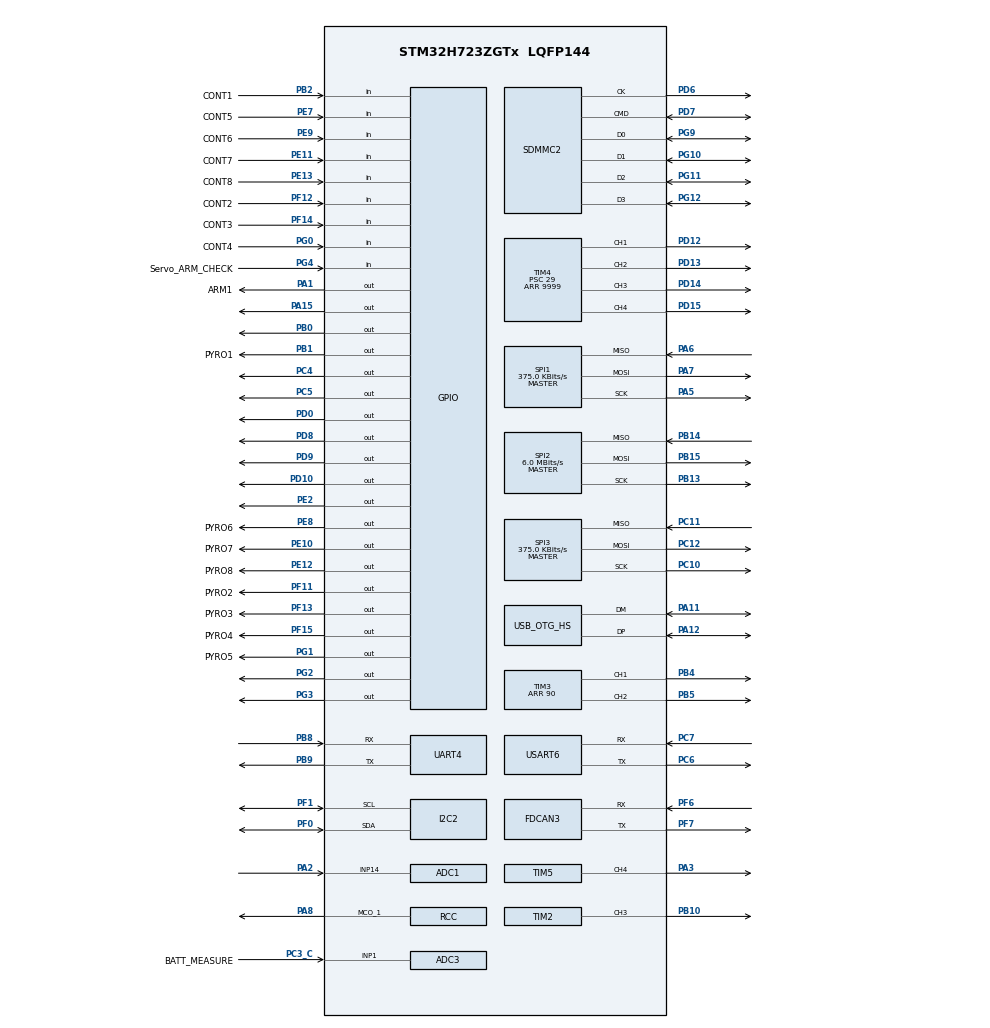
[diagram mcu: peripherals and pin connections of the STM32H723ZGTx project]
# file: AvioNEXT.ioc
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ADC1.Channel-0\#ChannelRegularConversion=ADC_CHANNEL_14
ADC1.ClockPrescaler=ADC_CLOCK_ASYNC_DIV256
ADC1.ClockPrescalerADC3=ADC_CLOCK_ASYNC_DIV256
ADC1.ContinuousConvMode=DISABLE
ADC1.NbrOfConversionFlag=1
ADC1.OffsetNumber-0\#ChannelRegularConversion=ADC_OFFSET_NONE
ADC1.OffsetSignedSaturation-0\#ChannelRegularConversion=DISABLE
ADC1.Rank-0\#ChannelRegularConversion=1
ADC1.SamplingTime-0\#ChannelRegularConversion=ADC_SAMPLETIME_16CYCLES_5
ADC1.master=1
ADC3.Channel-0\#ChannelRegularConversion=ADC_CHANNEL_1
ADC3.ClockPrescaler=ADC_CLOCK_ASYNC_DIV256
ADC3.ClockPrescalerADC3=ADC_CLOCK_ASYNC_DIV256
ADC3.ContinuousConvMode=DISABLE
ADC3.DMAContinuousRequests=ENABLE
ADC3.DiscontinuousConvMode=DISABLE
ADC3.NbrOfConversion=1
ADC3.NbrOfConversionFlag=1
ADC3.OffsetNumber-0\#ChannelRegularConversion=ADC_OFFSET_NONE
ADC3.OffsetSign-0\#ChannelRegularConversion=ADC3_OFFSET_SIGN_NEGATIVE
ADC3.Rank-0\#ChannelRegularConversion=1
ADC3.SamplingTime-0\#ChannelRegularConversion=ADC3_SAMPLETIME_2CYCLES_5
Dma.ADC1.5.Direction=DMA_PERIPH_TO_MEMORY
Dma.ADC1.5.EventEnable=DISABLE
Dma.ADC1.5.FIFOMode=DMA_FIFOMODE_DISABLE
Dma.ADC1.5.Instance=DMA1_Stream5
Dma.ADC1.5.MemDataAlignment=DMA_MDATAALIGN_HALFWORD
Dma.ADC1.5.MemInc=DMA_MINC_ENABLE
Dma.ADC1.5.Mode=DMA_NORMAL
Dma.ADC1.5.PeriphDataAlignment=DMA_PDATAALIGN_HALFWORD
Dma.ADC1.5.PeriphInc=DMA_PINC_DISABLE
Dma.ADC1.5.Polarity=HAL_DMAMUX_REQ_GEN_RISING
Dma.ADC1.5.Priority=DMA_PRIORITY_LOW
Dma.ADC1.5.RequestNumber=1
Dma.ADC1.5.SignalID=NONE
Dma.ADC1.5.SyncEnable=DISABLE
Dma.ADC1.5.SyncPolarity=HAL_DMAMUX_SYNC_NO_EVENT
Dma.ADC1.5.SyncRequestNumber=1
Dma.ADC1.5.SyncSignalID=NONE
Dma.ADC3.6.Direction=DMA_PERIPH_TO_MEMORY
Dma.ADC3.6.EventEnable=DISABLE
Dma.ADC3.6.FIFOMode=DMA_FIFOMODE_DISABLE
Dma.ADC3.6.Instance=DMA2_Stream7
Dma.ADC3.6.MemDataAlignment=DMA_MDATAALIGN_HALFWORD
Dma.ADC3.6.MemInc=DMA_MINC_ENABLE
Dma.ADC3.6.Mode=DMA_CIRCULAR
Dma.ADC3.6.PeriphDataAlignment=DMA_PDATAALIGN_HALFWORD
Dma.ADC3.6.PeriphInc=DMA_PINC_DISABLE
Dma.ADC3.6.Polarity=HAL_DMAMUX_REQ_GEN_RISING
Dma.ADC3.6.Priority=DMA_PRIORITY_MEDIUM
Dma.ADC3.6.RequestNumber=1
Dma.ADC3.6.SignalID=NONE
Dma.ADC3.6.SyncEnable=DISABLE
Dma.ADC3.6.SyncPolarity=HAL_DMAMUX_SYNC_NO_EVENT
Dma.ADC3.6.SyncRequestNumber=1
Dma.ADC3.6.SyncSignalID=NONE
Dma.Request0=TIM4_CH3
Dma.Request1=TIM2_CH3
Dma.Request2=TIM5_CH4
Dma.Request3=TIM3_CH2
Dma.Request4=TIM3_CH1
Dma.Request5=ADC1
Dma.Request6=ADC3
Dma.TIM2_CH3.1.Direction=DMA_MEMORY_TO_PERIPH
Dma.TIM2_CH3.1.EventEnable=DISABLE
Dma.TIM2_CH3.1.FIFOMode=DMA_FIFOMODE_DISABLE
Dma.TIM2_CH3.1.Instance=DMA1_Stream1
Dma.TIM2_CH3.1.MemDataAlignment=DMA_MDATAALIGN_WORD
Dma.TIM2_CH3.1.MemInc=DMA_MINC_ENABLE
Dma.TIM2_CH3.1.Mode=DMA_NORMAL
Dma.TIM2_CH3.1.PeriphDataAlignment=DMA_PDATAALIGN_WORD
Dma.TIM2_CH3.1.PeriphInc=DMA_PINC_DISABLE
Dma.TIM2_CH3.1.Polarity=HAL_DMAMUX_REQ_GEN_RISING
Dma.TIM2_CH3.1.Priority=DMA_PRIORITY_LOW
Dma.TIM2_CH3.1.RequestNumber=1
Dma.TIM2_CH3.1.SignalID=NONE
Dma.TIM2_CH3.1.SyncEnable=DISABLE
Dma.TIM2_CH3.1.SyncPolarity=HAL_DMAMUX_SYNC_NO_EVENT
Dma.TIM2_CH3.1.SyncRequestNumber=1
Dma.TIM2_CH3.1.SyncSignalID=NONE
Dma.TIM3_CH1.4.Direction=DMA_MEMORY_TO_PERIPH
Dma.TIM3_CH1.4.EventEnable=DISABLE
Dma.TIM3_CH1.4.FIFOMode=DMA_FIFOMODE_DISABLE
Dma.TIM3_CH1.4.Instance=DMA1_Stream4
Dma.TIM3_CH1.4.MemDataAlignment=DMA_MDATAALIGN_WORD
Dma.TIM3_CH1.4.MemInc=DMA_MINC_ENABLE
Dma.TIM3_CH1.4.Mode=DMA_NORMAL
Dma.TIM3_CH1.4.PeriphDataAlignment=DMA_PDATAALIGN_WORD
Dma.TIM3_CH1.4.PeriphInc=DMA_PINC_DISABLE
Dma.TIM3_CH1.4.Polarity=HAL_DMAMUX_REQ_GEN_RISING
Dma.TIM3_CH1.4.Priority=DMA_PRIORITY_LOW
Dma.TIM3_CH1.4.RequestNumber=1
Dma.TIM3_CH1.4.SignalID=NONE
Dma.TIM3_CH1.4.SyncEnable=DISABLE
Dma.TIM3_CH1.4.SyncPolarity=HAL_DMAMUX_SYNC_NO_EVENT
Dma.TIM3_CH1.4.SyncRequestNumber=1
Dma.TIM3_CH1.4.SyncSignalID=NONE
Dma.TIM3_CH2.3.Direction=DMA_MEMORY_TO_PERIPH
Dma.TIM3_CH2.3.EventEnable=DISABLE
Dma.TIM3_CH2.3.FIFOMode=DMA_FIFOMODE_DISABLE
Dma.TIM3_CH2.3.Instance=DMA1_Stream3
Dma.TIM3_CH2.3.MemDataAlignment=DMA_MDATAALIGN_WORD
Dma.TIM3_CH2.3.MemInc=DMA_MINC_ENABLE
Dma.TIM3_CH2.3.Mode=DMA_NORMAL
Dma.TIM3_CH2.3.PeriphDataAlignment=DMA_PDATAALIGN_WORD
Dma.TIM3_CH2.3.PeriphInc=DMA_PINC_DISABLE
Dma.TIM3_CH2.3.Polarity=HAL_DMAMUX_REQ_GEN_RISING
Dma.TIM3_CH2.3.Priority=DMA_PRIORITY_LOW
Dma.TIM3_CH2.3.RequestNumber=1
Dma.TIM3_CH2.3.SignalID=NONE
Dma.TIM3_CH2.3.SyncEnable=DISABLE
Dma.TIM3_CH2.3.SyncPolarity=HAL_DMAMUX_SYNC_NO_EVENT
Dma.TIM3_CH2.3.SyncRequestNumber=1
Dma.TIM3_CH2.3.SyncSignalID=NONE
Dma.TIM4_CH3.0.Direction=DMA_MEMORY_TO_PERIPH
Dma.TIM4_CH3.0.EventEnable=DISABLE
Dma.TIM4_CH3.0.FIFOMode=DMA_FIFOMODE_DISABLE
Dma.TIM4_CH3.0.Instance=DMA1_Stream0
Dma.TIM4_CH3.0.MemDataAlignment=DMA_MDATAALIGN_WORD
Dma.TIM4_CH3.0.MemInc=DMA_MINC_ENABLE
Dma.TIM4_CH3.0.Mode=DMA_NORMAL
Dma.TIM4_CH3.0.PeriphDataAlignment=DMA_PDATAALIGN_WORD
Dma.TIM4_CH3.0.PeriphInc=DMA_PINC_DISABLE
Dma.TIM4_CH3.0.Polarity=HAL_DMAMUX_REQ_GEN_RISING
Dma.TIM4_CH3.0.Priority=DMA_PRIORITY_LOW
Dma.TIM4_CH3.0.RequestNumber=1
Dma.TIM4_CH3.0.SignalID=NONE
Dma.TIM4_CH3.0.SyncEnable=DISABLE
Dma.TIM4_CH3.0.SyncPolarity=HAL_DMAMUX_SYNC_NO_EVENT
Dma.TIM4_CH3.0.SyncRequestNumber=1
Dma.TIM4_CH3.0.SyncSignalID=NONE
Dma.TIM5_CH4.2.Direction=DMA_MEMORY_TO_PERIPH
Dma.TIM5_CH4.2.EventEnable=DISABLE
Dma.TIM5_CH4.2.FIFOMode=DMA_FIFOMODE_DISABLE
Dma.TIM5_CH4.2.Instance=DMA1_Stream2
Dma.TIM5_CH4.2.MemDataAlignment=DMA_MDATAALIGN_WORD
Dma.TIM5_CH4.2.MemInc=DMA_MINC_ENABLE
Dma.TIM5_CH4.2.Mode=DMA_NORMAL
Dma.TIM5_CH4.2.PeriphDataAlignment=DMA_PDATAALIGN_WORD
Dma.TIM5_CH4.2.PeriphInc=DMA_PINC_DISABLE
Dma.TIM5_CH4.2.Polarity=HAL_DMAMUX_REQ_GEN_RISING
Dma.TIM5_CH4.2.Priority=DMA_PRIORITY_LOW
Dma.TIM5_CH4.2.RequestNumber=1
Dma.TIM5_CH4.2.SignalID=NONE
Dma.TIM5_CH4.2.SyncEnable=DISABLE
Dma.TIM5_CH4.2.SyncPolarity=HAL_DMAMUX_SYNC_NO_EVENT
Dma.TIM5_CH4.2.SyncRequestNumber=1
Dma.TIM5_CH4.2.SyncSignalID=NONE
FATFS.USE_DMA_CODE_SD=1
FATFS._MAX_SS=4096
FATFS._USE_LFN=1
FDCAN3.CalculateBaudRateNominal=500000
FDCAN3.CalculateTimeBitNominal=2000
FDCAN3.CalculateTimeQuantumNominal=400.0
FDCAN3.NominalPrescaler=20
FDCAN3.NominalTimeSeg1=2
FDCAN3.NominalTimeSeg2=2
FDCAN3.RxFifo0ElmtsNbr=1
I2C2.Timing=0x20303E5D
Mcu.Family=STM32H7
Mcu.Name=STM32H723ZGTx
Mcu.Package=LQFP144
NVIC.DMA1_Stream0_IRQn=true\:0\:0\:false\:false\:true\:false\:true\:true
NVIC.DMA1_Stream1_IRQn=true\:0\:0\:false\:false\:true\:false\:true\:true
NVIC.DMA1_Stream2_IRQn=true\:0\:0\:false\:false\:true\:false\:true\:true
NVIC.DMA1_Stream3_IRQn=true\:0\:0\:false\:false\:true\:false\:true\:true
NVIC.DMA1_Stream4_IRQn=true\:0\:0\:false\:false\:true\:false\:true\:true
NVIC.DMA1_Stream5_IRQn=true\:0\:0\:false\:false\:true\:false\:true\:true
NVIC.DMA2_Stream7_IRQn=true\:0\:0\:false\:false\:true\:false\:true\:true
NVIC.FDCAN3_IT0_IRQn=true\:0\:0\:false\:false\:true\:true\:true\:true
NVIC.I2C2_EV_IRQn=true\:1\:0\:true\:false\:true\:true\:true\:true
NVIC.OTG_HS_IRQn=true\:0\:0\:false\:false\:true\:false\:true\:true
NVIC.PriorityGroup=NVIC_PRIORITYGROUP_4
NVIC.SDMMC2_IRQn=true\:0\:0\:false\:false\:true\:true\:true\:true
NVIC.TIM4_IRQn=true\:0\:0\:false\:false\:true\:true\:true\:true
PA0.Signal=S_TIM2_CH1_ETR
PA1.GPIO_Label=ARM1
PA1.Signal=GPIO_Output
PA11.Mode=Device_Only_FS
PA11.Signal=USB_OTG_HS_DM
PA12.Mode=Device_Only_FS
PA12.Signal=USB_OTG_HS_DP
PA13(JTMS/SWDIO).Mode=Serial_Wire
PA13(JTMS/SWDIO).Signal=DEBUG_JTMS-SWDIO
PA14(JTCK/SWCLK).Mode=Serial_Wire
PA14(JTCK/SWCLK).Signal=DEBUG_JTCK-SWCLK
PA15(JTDI).Signal=GPIO_Output
PA2.Signal=ADCx_INP14
PA3.GPIO_PuPd=GPIO_PULLDOWN
PA3.Signal=S_TIM5_CH4
PA5.Mode=Full_Duplex_Master
PA5.Signal=SPI1_SCK
PA6.Mode=Full_Duplex_Master
PA6.Signal=SPI1_MISO
PA7.Mode=Full_Duplex_Master
PA7.Signal=SPI1_MOSI
PA8.Mode=Clock-out-1
PA8.Signal=RCC_MCO_1
PB0.Signal=GPIO_Output
PB1.GPIO_Label=PYRO1
PB1.Signal=GPIO_Output
PB10.GPIO_PuPd=GPIO_PULLDOWN
PB10.Signal=S_TIM2_CH3
PB13.Mode=Full_Duplex_Master
PB13.Signal=SPI2_SCK
PB14.Mode=Full_Duplex_Master
PB14.Signal=SPI2_MISO
PB15.Mode=Full_Duplex_Master
PB15.Signal=SPI2_MOSI
PB2.GPIO_Label=CONT1
PB2.GPIO_PuPd=GPIO_PULLUP
PB2.Signal=GPIO_Input
PB4(NJTRST).GPIO_PuPd=GPIO_PULLDOWN
PB4(NJTRST).Signal=S_TIM3_CH1
PB5.GPIO_PuPd=GPIO_PULLDOWN
PB5.Signal=S_TIM3_CH2
PB8.Mode=Asynchronous
PB8.Signal=UART4_RX
PB9.Mode=Asynchronous
PB9.Signal=UART4_TX
PC10.Mode=Full_Duplex_Master
PC10.Signal=SPI3_SCK
PC11.Mode=Full_Duplex_Master
PC11.Signal=SPI3_MISO
PC12.Mode=Full_Duplex_Master
PC12.Signal=SPI3_MOSI
PC3_C.GPIO_Label=BATT_MEASURE
PC3_C.Mode=IN1-Single-Ended
PC3_C.Signal=ADC3_INP1
PC4.Signal=GPIO_Output
PC5.Signal=GPIO_Output
PC6.Mode=Asynchronous
PC6.Signal=USART6_TX
PC7.Mode=Asynchronous
PC7.Signal=USART6_RX
PD0.Signal=GPIO_Output
PD10.PinState=GPIO_PIN_SET
PD10.Signal=GPIO_Output
PD12.Signal=S_TIM4_CH1
PD13.Signal=S_TIM4_CH2
PD14.GPIO_PuPd=GPIO_PULLDOWN
PD14.Signal=S_TIM4_CH3
PD15.Signal=S_TIM4_CH4
PD6.Mode=SD_4_bits_Wide_bus
PD6.Signal=SDMMC2_CK
PD7.GPIO_PuPd=GPIO_PULLUP
PD7.Mode=SD_4_bits_Wide_bus
PD7.Signal=SDMMC2_CMD
PD8.PinState=GPIO_PIN_SET
PD8.Signal=GPIO_Output
PD9.PinState=GPIO_PIN_SET
PD9.Signal=GPIO_Output
PE10.GPIO_Label=PYRO7
PE10.Signal=GPIO_Output
PE11.GPIO_Label=CONT7
PE11.GPIO_PuPd=GPIO_PULLUP
PE11.Signal=GPIO_Input
PE12.GPIO_Label=PYRO8
PE12.Signal=GPIO_Output
PE13.GPIO_Label=CONT8
PE13.GPIO_PuPd=GPIO_PULLUP
PE13.Signal=GPIO_Input
PE2.PinState=GPIO_PIN_RESET
PE2.Signal=GPIO_Output
PE7.GPIO_Label=CONT5
PE7.GPIO_PuPd=GPIO_PULLUP
PE7.Signal=GPIO_Input
PE8.GPIO_Label=PYRO6
PE8.Signal=GPIO_Output
PE9.GPIO_Label=CONT6
PE9.GPIO_PuPd=GPIO_PULLUP
PE9.Signal=GPIO_Input
PF0.Mode=I2C
PF0.Signal=I2C2_SDA
PF1.Mode=I2C
PF1.Signal=I2C2_SCL
PF11.GPIO_Label=PYRO2
PF11.Signal=GPIO_Output
PF12.GPIO_Label=CONT2
PF12.GPIO_PuPd=GPIO_PULLUP
PF12.Signal=GPIO_Input
PF13.GPIO_Label=PYRO3
PF13.Signal=GPIO_Output
PF14.GPIO_Label=CONT3
PF14.GPIO_PuPd=GPIO_PULLUP
PF14.Signal=GPIO_Input
PF15.GPIO_Label=PYRO4
PF15.Signal=GPIO_Output
PF6.Mode=FDCAN_Activate
PF6.Signal=FDCAN3_RX
PF7.Mode=FDCAN_Activate
PF7.Signal=FDCAN3_TX
PG0.GPIO_Label=CONT4
PG0.GPIO_PuPd=GPIO_PULLUP
PG0.Signal=GPIO_Input
PG1.GPIO_Label=PYRO5
PG1.Signal=GPIO_Output
PG10.Mode=SD_4_bits_Wide_bus
PG10.Signal=SDMMC2_D1
PG11.Mode=SD_4_bits_Wide_bus
PG11.Signal=SDMMC2_D2
PG12.Mode=SD_4_bits_Wide_bus
PG12.Signal=SDMMC2_D3
PG2.Signal=GPIO_Output
PG3.Signal=GPIO_Output
PG4.GPIO_Label=Servo_ARM_CHECK
PG4.Signal=GPIO_Input
PG9.GPIO_PuPd=GPIO_PULLUP
PG9.Mode=SD_4_bits_Wide_bus
PG9.Signal=SDMMC2_D0
ProjectManager.HeapSize=0x400
ProjectManager.StackSize=0x800
ProjectManager.TargetToolchain=STM32CubeIDE
RCC.ADCFreq_Value=48000000
RCC.APB1Freq_Value=50000000
RCC.APB2Freq_Value=50000000
RCC.APB3Freq_Value=100000000
RCC.APB4Freq_Value=100000000
RCC.CortexFreq_Value=200000000
RCC.D1PPRE=RCC_APB3_DIV2
RCC.D2PPRE1=RCC_APB1_DIV4
RCC.D2PPRE2=RCC_APB2_DIV4
RCC.D3PPRE=RCC_APB4_DIV2
RCC.DIVM1=4
RCC.DIVM2=4
RCC.DIVN1=12
RCC.DIVN2=12
RCC.DIVP1=1
RCC.DIVP2=4
RCC.DIVQ1=4
RCC.EnableHSE-ClockTree=true
RCC.HCLKFreq_Value=200000000
RCC.HSE_VALUE=50000000
RCC.PLL2FRACN=0
RCC.PLL2_VCO_SEL-AdvancedSettings=RCC_PLL2VCOMEDIUM
RCC.PLL3FRACN=0
RCC.PLL3_VCO_SEL-AdvancedSettings=RCC_PLL3VCOMEDIUM
RCC.PLLFRACN=4096
RCC.SPI123CLockSelection=RCC_SPI123CLKSOURCE_PLL2
RCC.SYSCLKFreq_VALUE=200000000
RCC.SYSCLKSource=RCC_SYSCLKSOURCE_PLLCLK
RCC.USBCLockSelection=RCC_USBCLKSOURCE_HSI48
RCC.USBFreq_Value=48000000
SDMMC2.ClockDiv=8
SH.ADCx_INP14.0=ADC1_INP14,IN14-Single-Ended
SH.S_TIM2_CH1_ETR.0=TIM2_CH1
SH.S_TIM2_CH3.0=TIM2_CH3,PWM Generation3 CH3
SH.S_TIM3_CH1.0=TIM3_CH1,PWM Generation1 CH1
SH.S_TIM3_CH2.0=TIM3_CH2,PWM Generation2 CH2
SH.S_TIM4_CH1.0=TIM4_CH1,PWM Generation1 CH1
SH.S_TIM4_CH2.0=TIM4_CH2,PWM Generation2 CH2
SH.S_TIM4_CH3.0=TIM4_CH3,PWM Generation3 CH3
SH.S_TIM4_CH4.0=TIM4_CH4,PWM Generation4 CH4
SH.S_TIM5_CH4.0=TIM5_CH4,PWM Generation4 CH4
SPI1.BaudRatePrescaler=SPI_BAUDRATEPRESCALER_128
SPI1.CalculateBaudRate=375.0 KBits/s
SPI1.DataSize=SPI_DATASIZE_8BIT
SPI1.Direction=SPI_DIRECTION_2LINES
SPI1.Mode=SPI_MODE_MASTER
SPI1.VirtualType=VM_MASTER
SPI2.BaudRatePrescaler=SPI_BAUDRATEPRESCALER_8
SPI2.CalculateBaudRate=6.0 MBits/s
SPI2.DataSize=SPI_DATASIZE_8BIT
SPI2.Direction=SPI_DIRECTION_2LINES
SPI2.Mode=SPI_MODE_MASTER
SPI2.VirtualType=VM_MASTER
SPI3.BaudRatePrescaler=SPI_BAUDRATEPRESCALER_128
SPI3.CalculateBaudRate=375.0 KBits/s
SPI3.DataSize=SPI_DATASIZE_8BIT
SPI3.Direction=SPI_DIRECTION_2LINES
SPI3.Mode=SPI_MODE_MASTER
SPI3.VirtualType=VM_MASTER
TIM13.Prescaler=99
TIM2.Channel-PWM\ Generation3\ CH3=TIM_CHANNEL_3
TIM2.Period=90
TIM3.Channel-PWM\ Generation1\ CH1=TIM_CHANNEL_1
TIM3.Channel-PWM\ Generation2\ CH2=TIM_CHANNEL_2
TIM3.Period=90
TIM4.Channel-PWM\ Generation1\ CH1=TIM_CHANNEL_1
TIM4.Channel-PWM\ Generation2\ CH2=TIM_CHANNEL_2
TIM4.Channel-PWM\ Generation3\ CH3=TIM_CHANNEL_3
TIM4.Channel-PWM\ Generation4\ CH4=TIM_CHANNEL_4
TIM4.OCFastMode_PWM-PWM\ Generation3\ CH3=TIM_OCFAST_DISABLE
TIM4.Period=9999
TIM4.Prescaler=29
TIM5.Channel-PWM\ Generation4\ CH4=TIM_CHANNEL_4
TIM5.Period=90
USART6.VirtualMode-Asynchronous=VM_ASYNC
USB_DEVICE.CLASS_NAME_HS=CDC
USB_DEVICE.MANUFACTURER_STRING=ARC
USB_DEVICE.PRODUCT_STRING_CDC_HS=AvioNEXT Flight Computer
USB_DEVICE.VirtualMode=Cdc
USB_DEVICE.VirtualModeHS=Cdc_HS
USB_OTG_HS.VirtualMode-Device_Only_FS=Device_Only_FS
VP_FATFS_VS_SDIO.Mode=SDIO
VP_TIM13_VS_ClockSourceINT.Mode=Enable_Timer
VP_USB_DEVICE_VS_USB_DEVICE_CDC_HS.Mode=CDC_HS
board=custom

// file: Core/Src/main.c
/* USER CODE BEGIN Header */
/**
 ******************************************************************************
 * @file           : main.c
 * @brief          : Main program body
 ******************************************************************************
 * @attention
 *
 * Copyright (c) 2024 STMicroelectronics.
 * All rights reserved.
 *
 * This software is licensed under terms that can be found in the LICENSE file
 * in the root directory of this software component.
 * If no LICENSE file comes with this software, it is provided AS-IS.
 *
 ******************************************************************************
 */
/* USER CODE END Header */
#include "main.h"
#include "fatfs.h"
#include "usb_device.h"

/* USER CODE BEGIN Includes */
//#include "AvioNEXT.h"
//#include "LG_IMU.h"
//#include "max_m10s.h"
//#include "StatusDisplay.h"
#include "LoRA.h"
/* USER CODE END Includes */

/* USER CODE BEGIN PD */

uint16_t DMA_data;

uint16_t read_Data;
/* USER CODE END PD */

ADC_HandleTypeDef hadc1;
ADC_HandleTypeDef hadc3;
DMA_HandleTypeDef hdma_adc1;
DMA_HandleTypeDef hdma_adc3;

FDCAN_HandleTypeDef hfdcan3;

I2C_HandleTypeDef hi2c2;

SD_HandleTypeDef hsd2;

SPI_HandleTypeDef hspi1;
SPI_HandleTypeDef hspi2;
SPI_HandleTypeDef hspi3;

TIM_HandleTypeDef htim2;
TIM_HandleTypeDef htim3;
TIM_HandleTypeDef htim4;
TIM_HandleTypeDef htim5;
TIM_HandleTypeDef htim13;
DMA_HandleTypeDef hdma_tim2_ch3;
DMA_HandleTypeDef hdma_tim3_ch2;
DMA_HandleTypeDef hdma_tim3_ch1;
DMA_HandleTypeDef hdma_tim4_ch3;
DMA_HandleTypeDef hdma_tim5_ch4;

UART_HandleTypeDef huart4;
UART_HandleTypeDef huart6;

void SystemClock_Config(void);
void PeriphCommonClock_Config(void);
static void MX_GPIO_Init(void);
static void MX_DMA_Init(void);
static void MX_SPI3_Init(void);
static void MX_FDCAN3_Init(void);
static void MX_USART6_UART_Init(void);
static void MX_ADC1_Init(void);
static void MX_TIM4_Init(void);
static void MX_ADC3_Init(void);
static void MX_SPI2_Init(void);
static void MX_I2C2_Init(void);
static void MX_TIM2_Init(void);
static void MX_TIM5_Init(void);
static void MX_TIM3_Init(void);
static void MX_SPI1_Init(void);
static void MX_UART4_Init(void);
static void MX_SDMMC2_SD_Init(void);
static void MX_TIM13_Init(void);

int main(void)
{

  /* MCU Configuration--------------------------------------------------------*/

  /* Reset of all peripherals, Initializes the Flash interface and the Systick. */
  HAL_Init();

  /* Configure the system clock */
  SystemClock_Config();

/* Configure the peripherals common clocks */
  PeriphCommonClock_Config();

  /* Initialize all configured peripherals */
  MX_GPIO_Init();
  MX_DMA_Init();
  MX_SPI3_Init();
  MX_FDCAN3_Init();
  MX_USART6_UART_Init();
  MX_ADC1_Init();
  MX_TIM4_Init();
  MX_ADC3_Init();
  MX_SPI2_Init();
  MX_I2C2_Init();
  MX_TIM2_Init();
  MX_TIM5_Init();
  MX_TIM3_Init();
  MX_USB_DEVICE_Init();
  MX_SPI1_Init();
  MX_UART4_Init();
  MX_FATFS_Init();
  MX_SDMMC2_SD_Init();
  MX_TIM13_Init();
  /* USER CODE BEGIN 2 */
  LoRA_begin(86000000);

  /* USER CODE END 2 */

  /* Infinite loop */
  /* USER CODE BEGIN WHILE */
	while (1) {
		char LoRA_data[255];

		if(recv_packet(LoRA_data, 255)){
			char print_data[400];
			sprintf(print_data, "\nRadio Packet received:\n%s\n----------------", LoRA_data);
			CDC_Transmit_HS(print_data, strlen(print_data));
		}
		HAL_Delay(100);
	}

    /* USER CODE END WHILE */

}

void SystemClock_Config(void)
{
  RCC_OscInitTypeDef RCC_OscInitStruct = {0};
  RCC_ClkInitTypeDef RCC_ClkInitStruct = {0};

  /** Supply configuration update enable
  */
  HAL_PWREx_ConfigSupply(PWR_LDO_SUPPLY);

  /** Configure the main internal regulator output voltage
  */
  __HAL_PWR_VOLTAGESCALING_CONFIG(PWR_REGULATOR_VOLTAGE_SCALE2);

  while(!__HAL_PWR_GET_FLAG(PWR_FLAG_VOSRDY)) {}

  /** Initializes the RCC Oscillators according to the specified parameters
  * in the RCC_OscInitTypeDef structure.
  */
  RCC_OscInitStruct.OscillatorType = RCC_OSCILLATORTYPE_HSI48|RCC_OSCILLATORTYPE_HSI;
  RCC_OscInitStruct.HSIState = RCC_HSI_DIV1;
  RCC_OscInitStruct.HSICalibrationValue = 64;
  RCC_OscInitStruct.HSI48State = RCC_HSI48_ON;
  RCC_OscInitStruct.PLL.PLLState = RCC_PLL_ON;
  RCC_OscInitStruct.PLL.PLLSource = RCC_PLLSOURCE_HSI;
  RCC_OscInitStruct.PLL.PLLM = 4;
  RCC_OscInitStruct.PLL.PLLN = 12;
  RCC_OscInitStruct.PLL.PLLP = 1;
  RCC_OscInitStruct.PLL.PLLQ = 3;
  RCC_OscInitStruct.PLL.PLLR = 2;
  RCC_OscInitStruct.PLL.PLLRGE = RCC_PLL1VCIRANGE_3;
  RCC_OscInitStruct.PLL.PLLVCOSEL = RCC_PLL1VCOWIDE;
  RCC_OscInitStruct.PLL.PLLFRACN = 0;
  if (HAL_RCC_OscConfig(&RCC_OscInitStruct) != HAL_OK)
  {
    Error_Handler();
  }

  /** Initializes the CPU, AHB and APB buses clocks
  */
  RCC_ClkInitStruct.ClockType = RCC_CLOCKTYPE_HCLK|RCC_CLOCKTYPE_SYSCLK
                              |RCC_CLOCKTYPE_PCLK1|RCC_CLOCKTYPE_PCLK2
                              |RCC_CLOCKTYPE_D3PCLK1|RCC_CLOCKTYPE_D1PCLK1;
  RCC_ClkInitStruct.SYSCLKSource = RCC_SYSCLKSOURCE_PLLCLK;
  RCC_ClkInitStruct.SYSCLKDivider = RCC_SYSCLK_DIV1;
  RCC_ClkInitStruct.AHBCLKDivider = RCC_HCLK_DIV2;
  RCC_ClkInitStruct.APB3CLKDivider = RCC_APB3_DIV2;
  RCC_ClkInitStruct.APB1CLKDivider = RCC_APB1_DIV2;
  RCC_ClkInitStruct.APB2CLKDivider = RCC_APB2_DIV2;
  RCC_ClkInitStruct.APB4CLKDivider = RCC_APB4_DIV2;

  if (HAL_RCC_ClockConfig(&RCC_ClkInitStruct, FLASH_LATENCY_1) != HAL_OK)
  {
    Error_Handler();
  }
  HAL_RCC_MCOConfig(RCC_MCO1, RCC_MCO1SOURCE_HSI, RCC_MCODIV_1);
}

void PeriphCommonClock_Config(void)
{
  RCC_PeriphCLKInitTypeDef PeriphClkInitStruct = {0};

  /** Initializes the peripherals clock
  */
  PeriphClkInitStruct.PeriphClockSelection = RCC_PERIPHCLK_ADC|RCC_PERIPHCLK_SPI3
                              |RCC_PERIPHCLK_SPI2|RCC_PERIPHCLK_SPI1;
  PeriphClkInitStruct.PLL2.PLL2M = 4;
  PeriphClkInitStruct.PLL2.PLL2N = 12;
  PeriphClkInitStruct.PLL2.PLL2P = 4;
  PeriphClkInitStruct.PLL2.PLL2Q = 2;
  PeriphClkInitStruct.PLL2.PLL2R = 2;
  PeriphClkInitStruct.PLL2.PLL2RGE = RCC_PLL2VCIRANGE_3;
  PeriphClkInitStruct.PLL2.PLL2VCOSEL = RCC_PLL2VCOWIDE;
  PeriphClkInitStruct.PLL2.PLL2FRACN = 0;
  PeriphClkInitStruct.Spi123ClockSelection = RCC_SPI123CLKSOURCE_PLL2;
  PeriphClkInitStruct.AdcClockSelection = RCC_ADCCLKSOURCE_PLL2;
  if (HAL_RCCEx_PeriphCLKConfig(&PeriphClkInitStruct) != HAL_OK)
  {
    Error_Handler();
  }
}

static void MX_ADC1_Init(void)
{

  ADC_MultiModeTypeDef multimode = {0};
  ADC_ChannelConfTypeDef sConfig = {0};

  /** Common config
  */
  hadc1.Instance = ADC1;
  hadc1.Init.ClockPrescaler = ADC_CLOCK_ASYNC_DIV256;
  hadc1.Init.Resolution = ADC_RESOLUTION_16B;
  hadc1.Init.ScanConvMode = ADC_SCAN_DISABLE;
  hadc1.Init.EOCSelection = ADC_EOC_SINGLE_CONV;
  hadc1.Init.LowPowerAutoWait = DISABLE;
  hadc1.Init.ContinuousConvMode = DISABLE;
  hadc1.Init.NbrOfConversion = 1;
  hadc1.Init.DiscontinuousConvMode = DISABLE;
  hadc1.Init.ExternalTrigConv = ADC_SOFTWARE_START;
  hadc1.Init.ExternalTrigConvEdge = ADC_EXTERNALTRIGCONVEDGE_NONE;
  hadc1.Init.ConversionDataManagement = ADC_CONVERSIONDATA_DR;
  hadc1.Init.Overrun = ADC_OVR_DATA_PRESERVED;
  hadc1.Init.LeftBitShift = ADC_LEFTBITSHIFT_NONE;
  hadc1.Init.OversamplingMode = DISABLE;
  if (HAL_ADC_Init(&hadc1) != HAL_OK)
  {
    Error_Handler();
  }

  /** Configure the ADC multi-mode
  */
  multimode.Mode = ADC_MODE_INDEPENDENT;
  if (HAL_ADCEx_MultiModeConfigChannel(&hadc1, &multimode) != HAL_OK)
  {
    Error_Handler();
  }

  /** Configure Regular Channel
  */
  sConfig.Channel = ADC_CHANNEL_14;
  sConfig.Rank = ADC_REGULAR_RANK_1;
  sConfig.SamplingTime = ADC_SAMPLETIME_16CYCLES_5;
  sConfig.SingleDiff = ADC_SINGLE_ENDED;
  sConfig.OffsetNumber = ADC_OFFSET_NONE;
  sConfig.Offset = 0;
  sConfig.OffsetSignedSaturation = DISABLE;
  if (HAL_ADC_ConfigChannel(&hadc1, &sConfig) != HAL_OK)
  {
    Error_Handler();
  }

}

static void MX_ADC3_Init(void)
{

  ADC_ChannelConfTypeDef sConfig = {0};

  /** Common config
  */
  hadc3.Instance = ADC3;
  hadc3.Init.ClockPrescaler = ADC_CLOCK_ASYNC_DIV256;
  hadc3.Init.Resolution = ADC_RESOLUTION_12B;
  hadc3.Init.DataAlign = ADC3_DATAALIGN_RIGHT;
  hadc3.Init.ScanConvMode = ADC_SCAN_DISABLE;
  hadc3.Init.EOCSelection = ADC_EOC_SINGLE_CONV;
  hadc3.Init.LowPowerAutoWait = DISABLE;
  hadc3.Init.ContinuousConvMode = DISABLE;
  hadc3.Init.NbrOfConversion = 1;
  hadc3.Init.DiscontinuousConvMode = DISABLE;
  hadc3.Init.ExternalTrigConv = ADC_SOFTWARE_START;
  hadc3.Init.ExternalTrigConvEdge = ADC_EXTERNALTRIGCONVEDGE_NONE;
  hadc3.Init.DMAContinuousRequests = ENABLE;
  hadc3.Init.SamplingMode = ADC_SAMPLING_MODE_NORMAL;
  hadc3.Init.ConversionDataManagement = ADC_CONVERSIONDATA_DR;
  hadc3.Init.Overrun = ADC_OVR_DATA_PRESERVED;
  hadc3.Init.LeftBitShift = ADC_LEFTBITSHIFT_NONE;
  hadc3.Init.OversamplingMode = DISABLE;
  if (HAL_ADC_Init(&hadc3) != HAL_OK)
  {
    Error_Handler();
  }

  /** Configure Regular Channel
  */
  sConfig.Channel = ADC_CHANNEL_1;
  sConfig.Rank = ADC_REGULAR_RANK_1;
  sConfig.SamplingTime = ADC3_SAMPLETIME_2CYCLES_5;
  sConfig.SingleDiff = ADC_SINGLE_ENDED;
  sConfig.OffsetNumber = ADC_OFFSET_NONE;
  sConfig.Offset = 0;
  sConfig.OffsetSign = ADC3_OFFSET_SIGN_NEGATIVE;
  if (HAL_ADC_ConfigChannel(&hadc3, &sConfig) != HAL_OK)
  {
    Error_Handler();
  }

}

static void MX_FDCAN3_Init(void)
{

  hfdcan3.Instance = FDCAN3;
  hfdcan3.Init.FrameFormat = FDCAN_FRAME_CLASSIC;
  hfdcan3.Init.Mode = FDCAN_MODE_NORMAL;
  hfdcan3.Init.AutoRetransmission = DISABLE;
  hfdcan3.Init.TransmitPause = DISABLE;
  hfdcan3.Init.ProtocolException = DISABLE;
  hfdcan3.Init.NominalPrescaler = 16;
  hfdcan3.Init.NominalSyncJumpWidth = 1;
  hfdcan3.Init.NominalTimeSeg1 = 2;
  hfdcan3.Init.NominalTimeSeg2 = 2;
  hfdcan3.Init.DataPrescaler = 1;
  hfdcan3.Init.DataSyncJumpWidth = 1;
  hfdcan3.Init.DataTimeSeg1 = 1;
  hfdcan3.Init.DataTimeSeg2 = 1;
  hfdcan3.Init.MessageRAMOffset = 0;
  hfdcan3.Init.StdFiltersNbr = 0;
  hfdcan3.Init.ExtFiltersNbr = 0;
  hfdcan3.Init.RxFifo0ElmtsNbr = 0;
  hfdcan3.Init.RxFifo0ElmtSize = FDCAN_DATA_BYTES_8;
  hfdcan3.Init.RxFifo1ElmtsNbr = 0;
  hfdcan3.Init.RxFifo1ElmtSize = FDCAN_DATA_BYTES_8;
  hfdcan3.Init.RxBuffersNbr = 0;
  hfdcan3.Init.RxBufferSize = FDCAN_DATA_BYTES_8;
  hfdcan3.Init.TxEventsNbr = 0;
  hfdcan3.Init.TxBuffersNbr = 0;
  hfdcan3.Init.TxFifoQueueElmtsNbr = 0;
  hfdcan3.Init.TxFifoQueueMode = FDCAN_TX_FIFO_OPERATION;
  hfdcan3.Init.TxElmtSize = FDCAN_DATA_BYTES_8;
  if (HAL_FDCAN_Init(&hfdcan3) != HAL_OK)
  {
    Error_Handler();
  }

}

static void MX_I2C2_Init(void)
{

  hi2c2.Instance = I2C2;
  hi2c2.Init.Timing = 0x20303E5D;
  hi2c2.Init.OwnAddress1 = 0;
  hi2c2.Init.AddressingMode = I2C_ADDRESSINGMODE_7BIT;
  hi2c2.Init.DualAddressMode = I2C_DUALADDRESS_DISABLE;
  hi2c2.Init.OwnAddress2 = 0;
  hi2c2.Init.OwnAddress2Masks = I2C_OA2_NOMASK;
  hi2c2.Init.GeneralCallMode = I2C_GENERALCALL_DISABLE;
  hi2c2.Init.NoStretchMode = I2C_NOSTRETCH_DISABLE;
  if (HAL_I2C_Init(&hi2c2) != HAL_OK)
  {
    Error_Handler();
  }

  /** Configure Analogue filter
  */
  if (HAL_I2CEx_ConfigAnalogFilter(&hi2c2, I2C_ANALOGFILTER_ENABLE) != HAL_OK)
  {
    Error_Handler();
  }

  /** Configure Digital filter
  */
  if (HAL_I2CEx_ConfigDigitalFilter(&hi2c2, 0) != HAL_OK)
  {
    Error_Handler();
  }

}

static void MX_SDMMC2_SD_Init(void)
{

  hsd2.Instance = SDMMC2;
  hsd2.Init.ClockEdge = SDMMC_CLOCK_EDGE_RISING;
  hsd2.Init.ClockPowerSave = SDMMC_CLOCK_POWER_SAVE_DISABLE;
  hsd2.Init.BusWide = SDMMC_BUS_WIDE_4B;
  hsd2.Init.HardwareFlowControl = SDMMC_HARDWARE_FLOW_CONTROL_DISABLE;
  hsd2.Init.ClockDiv = 8;

}

static void MX_SPI1_Init(void)
{

  /* SPI1 parameter configuration*/
  hspi1.Instance = SPI1;
  hspi1.Init.Mode = SPI_MODE_MASTER;
  hspi1.Init.Direction = SPI_DIRECTION_2LINES;
  hspi1.Init.DataSize = SPI_DATASIZE_8BIT;
  hspi1.Init.CLKPolarity = SPI_POLARITY_LOW;
  hspi1.Init.CLKPhase = SPI_PHASE_1EDGE;
  hspi1.Init.NSS = SPI_NSS_SOFT;
  hspi1.Init.BaudRatePrescaler = SPI_BAUDRATEPRESCALER_128;
  hspi1.Init.FirstBit = SPI_FIRSTBIT_MSB;
  hspi1.Init.TIMode = SPI_TIMODE_DISABLE;
  hspi1.Init.CRCCalculation = SPI_CRCCALCULATION_DISABLE;
  hspi1.Init.CRCPolynomial = 0x0;
  hspi1.Init.NSSPMode = SPI_NSS_PULSE_ENABLE;
  hspi1.Init.NSSPolarity = SPI_NSS_POLARITY_LOW;
  hspi1.Init.FifoThreshold = SPI_FIFO_THRESHOLD_01DATA;
  hspi1.Init.TxCRCInitializationPattern = SPI_CRC_INITIALIZATION_ALL_ZERO_PATTERN;
  hspi1.Init.RxCRCInitializationPattern = SPI_CRC_INITIALIZATION_ALL_ZERO_PATTERN;
  hspi1.Init.MasterSSIdleness = SPI_MASTER_SS_IDLENESS_00CYCLE;
  hspi1.Init.MasterInterDataIdleness = SPI_MASTER_INTERDATA_IDLENESS_00CYCLE;
  hspi1.Init.MasterReceiverAutoSusp = SPI_MASTER_RX_AUTOSUSP_DISABLE;
  hspi1.Init.MasterKeepIOState = SPI_MASTER_KEEP_IO_STATE_DISABLE;
  hspi1.Init.IOSwap = SPI_IO_SWAP_DISABLE;
  if (HAL_SPI_Init(&hspi1) != HAL_OK)
  {
    Error_Handler();
  }

}

static void MX_SPI2_Init(void)
{

  /* SPI2 parameter configuration*/
  hspi2.Instance = SPI2;
  hspi2.Init.Mode = SPI_MODE_MASTER;
  hspi2.Init.Direction = SPI_DIRECTION_2LINES;
  hspi2.Init.DataSize = SPI_DATASIZE_8BIT;
  hspi2.Init.CLKPolarity = SPI_POLARITY_LOW;
  hspi2.Init.CLKPhase = SPI_PHASE_1EDGE;
  hspi2.Init.NSS = SPI_NSS_SOFT;
  hspi2.Init.BaudRatePrescaler = SPI_BAUDRATEPRESCALER_8;
  hspi2.Init.FirstBit = SPI_FIRSTBIT_MSB;
  hspi2.Init.TIMode = SPI_TIMODE_DISABLE;
  hspi2.Init.CRCCalculation = SPI_CRCCALCULATION_DISABLE;
  hspi2.Init.CRCPolynomial = 0x0;
  hspi2.Init.NSSPMode = SPI_NSS_PULSE_ENABLE;
  hspi2.Init.NSSPolarity = SPI_NSS_POLARITY_LOW;
  hspi2.Init.FifoThreshold = SPI_FIFO_THRESHOLD_01DATA;
  hspi2.Init.TxCRCInitializationPattern = SPI_CRC_INITIALIZATION_ALL_ZERO_PATTERN;
  hspi2.Init.RxCRCInitializationPattern = SPI_CRC_INITIALIZATION_ALL_ZERO_PATTERN;
  hspi2.Init.MasterSSIdleness = SPI_MASTER_SS_IDLENESS_00CYCLE;
  hspi2.Init.MasterInterDataIdleness = SPI_MASTER_INTERDATA_IDLENESS_00CYCLE;
  hspi2.Init.MasterReceiverAutoSusp = SPI_MASTER_RX_AUTOSUSP_DISABLE;
  hspi2.Init.MasterKeepIOState = SPI_MASTER_KEEP_IO_STATE_DISABLE;
  hspi2.Init.IOSwap = SPI_IO_SWAP_DISABLE;
  if (HAL_SPI_Init(&hspi2) != HAL_OK)
  {
    Error_Handler();
  }

}

static void MX_SPI3_Init(void)
{

  /* SPI3 parameter configuration*/
  hspi3.Instance = SPI3;
  hspi3.Init.Mode = SPI_MODE_MASTER;
  hspi3.Init.Direction = SPI_DIRECTION_2LINES;
  hspi3.Init.DataSize = SPI_DATASIZE_8BIT;
  hspi3.Init.CLKPolarity = SPI_POLARITY_LOW;
  hspi3.Init.CLKPhase = SPI_PHASE_1EDGE;
  hspi3.Init.NSS = SPI_NSS_SOFT;
  hspi3.Init.BaudRatePrescaler = SPI_BAUDRATEPRESCALER_128;
  hspi3.Init.FirstBit = SPI_FIRSTBIT_MSB;
  hspi3.Init.TIMode = SPI_TIMODE_DISABLE;
  hspi3.Init.CRCCalculation = SPI_CRCCALCULATION_DISABLE;
  hspi3.Init.CRCPolynomial = 0x0;
  hspi3.Init.NSSPMode = SPI_NSS_PULSE_ENABLE;
  hspi3.Init.NSSPolarity = SPI_NSS_POLARITY_LOW;
  hspi3.Init.FifoThreshold = SPI_FIFO_THRESHOLD_01DATA;
  hspi3.Init.TxCRCInitializationPattern = SPI_CRC_INITIALIZATION_ALL_ZERO_PATTERN;
  hspi3.Init.RxCRCInitializationPattern = SPI_CRC_INITIALIZATION_ALL_ZERO_PATTERN;
  hspi3.Init.MasterSSIdleness = SPI_MASTER_SS_IDLENESS_00CYCLE;
  hspi3.Init.MasterInterDataIdleness = SPI_MASTER_INTERDATA_IDLENESS_00CYCLE;
  hspi3.Init.MasterReceiverAutoSusp = SPI_MASTER_RX_AUTOSUSP_DISABLE;
  hspi3.Init.MasterKeepIOState = SPI_MASTER_KEEP_IO_STATE_DISABLE;
  hspi3.Init.IOSwap = SPI_IO_SWAP_DISABLE;
  if (HAL_SPI_Init(&hspi3) != HAL_OK)
  {
    Error_Handler();
  }

}

static void MX_TIM2_Init(void)
{

  TIM_MasterConfigTypeDef sMasterConfig = {0};
  TIM_OC_InitTypeDef sConfigOC = {0};

  htim2.Instance = TIM2;
  htim2.Init.Prescaler = 0;
  htim2.Init.CounterMode = TIM_COUNTERMODE_UP;
  htim2.Init.Period = 90;
  htim2.Init.ClockDivision = TIM_CLOCKDIVISION_DIV1;
  htim2.Init.AutoReloadPreload = TIM_AUTORELOAD_PRELOAD_DISABLE;
  if (HAL_TIM_PWM_Init(&htim2) != HAL_OK)
  {
    Error_Handler();
  }
  sMasterConfig.MasterOutputTrigger = TIM_TRGO_RESET;
  sMasterConfig.MasterSlaveMode = TIM_MASTERSLAVEMODE_DISABLE;
  if (HAL_TIMEx_MasterConfigSynchronization(&htim2, &sMasterConfig) != HAL_OK)
  {
    Error_Handler();
  }
  sConfigOC.OCMode = TIM_OCMODE_PWM1;
  sConfigOC.Pulse = 0;
  sConfigOC.OCPolarity = TIM_OCPOLARITY_HIGH;
  sConfigOC.OCFastMode = TIM_OCFAST_DISABLE;
  if (HAL_TIM_PWM_ConfigChannel(&htim2, &sConfigOC, TIM_CHANNEL_3) != HAL_OK)
  {
    Error_Handler();
  }
  HAL_TIM_MspPostInit(&htim2);

}

static void MX_TIM3_Init(void)
{

  TIM_MasterConfigTypeDef sMasterConfig = {0};
  TIM_OC_InitTypeDef sConfigOC = {0};

  htim3.Instance = TIM3;
  htim3.Init.Prescaler = 0;
  htim3.Init.CounterMode = TIM_COUNTERMODE_UP;
  htim3.Init.Period = 90;
  htim3.Init.ClockDivision = TIM_CLOCKDIVISION_DIV1;
  htim3.Init.AutoReloadPreload = TIM_AUTORELOAD_PRELOAD_DISABLE;
  if (HAL_TIM_PWM_Init(&htim3) != HAL_OK)
  {
    Error_Handler();
  }
  sMasterConfig.MasterOutputTrigger = TIM_TRGO_RESET;
  sMasterConfig.MasterSlaveMode = TIM_MASTERSLAVEMODE_DISABLE;
  if (HAL_TIMEx_MasterConfigSynchronization(&htim3, &sMasterConfig) != HAL_OK)
  {
    Error_Handler();
  }
  sConfigOC.OCMode = TIM_OCMODE_PWM1;
  sConfigOC.Pulse = 0;
  sConfigOC.OCPolarity = TIM_OCPOLARITY_HIGH;
  sConfigOC.OCFastMode = TIM_OCFAST_DISABLE;
  if (HAL_TIM_PWM_ConfigChannel(&htim3, &sConfigOC, TIM_CHANNEL_1) != HAL_OK)
  {
    Error_Handler();
  }
  if (HAL_TIM_PWM_ConfigChannel(&htim3, &sConfigOC, TIM_CHANNEL_2) != HAL_OK)
  {
    Error_Handler();
  }
  HAL_TIM_MspPostInit(&htim3);

}

static void MX_TIM4_Init(void)
{

  TIM_MasterConfigTypeDef sMasterConfig = {0};
  TIM_OC_InitTypeDef sConfigOC = {0};

  htim4.Instance = TIM4;
  htim4.Init.Prescaler = 29;
  htim4.Init.CounterMode = TIM_COUNTERMODE_UP;
  htim4.Init.Period = 9999;
  htim4.Init.ClockDivision = TIM_CLOCKDIVISION_DIV1;
  htim4.Init.AutoReloadPreload = TIM_AUTORELOAD_PRELOAD_DISABLE;
  if (HAL_TIM_PWM_Init(&htim4) != HAL_OK)
  {
    Error_Handler();
  }
  sMasterConfig.MasterOutputTrigger = TIM_TRGO_RESET;
  sMasterConfig.MasterSlaveMode = TIM_MASTERSLAVEMODE_DISABLE;
  if (HAL_TIMEx_MasterConfigSynchronization(&htim4, &sMasterConfig) != HAL_OK)
  {
    Error_Handler();
  }
  sConfigOC.OCMode = TIM_OCMODE_PWM1;
  sConfigOC.Pulse = 0;
  sConfigOC.OCPolarity = TIM_OCPOLARITY_HIGH;
  sConfigOC.OCFastMode = TIM_OCFAST_DISABLE;
  if (HAL_TIM_PWM_ConfigChannel(&htim4, &sConfigOC, TIM_CHANNEL_1) != HAL_OK)
  {
    Error_Handler();
  }
  if (HAL_TIM_PWM_ConfigChannel(&htim4, &sConfigOC, TIM_CHANNEL_2) != HAL_OK)
  {
    Error_Handler();
  }
  if (HAL_TIM_PWM_ConfigChannel(&htim4, &sConfigOC, TIM_CHANNEL_3) != HAL_OK)
  {
    Error_Handler();
  }
  if (HAL_TIM_PWM_ConfigChannel(&htim4, &sConfigOC, TIM_CHANNEL_4) != HAL_OK)
  {
    Error_Handler();
  }
  HAL_TIM_MspPostInit(&htim4);

}

static void MX_TIM5_Init(void)
{

  TIM_MasterConfigTypeDef sMasterConfig = {0};
  TIM_OC_InitTypeDef sConfigOC = {0};

  htim5.Instance = TIM5;
  htim5.Init.Prescaler = 0;
  htim5.Init.CounterMode = TIM_COUNTERMODE_UP;
  htim5.Init.Period = 90;
  htim5.Init.ClockDivision = TIM_CLOCKDIVISION_DIV1;
  htim5.Init.AutoReloadPreload = TIM_AUTORELOAD_PRELOAD_DISABLE;
  if (HAL_TIM_PWM_Init(&htim5) != HAL_OK)
  {
    Error_Handler();
  }
  sMasterConfig.MasterOutputTrigger = TIM_TRGO_RESET;
  sMasterConfig.MasterSlaveMode = TIM_MASTERSLAVEMODE_DISABLE;
  if (HAL_TIMEx_MasterConfigSynchronization(&htim5, &sMasterConfig) != HAL_OK)
  {
    Error_Handler();
  }
  sConfigOC.OCMode = TIM_OCMODE_PWM1;
  sConfigOC.Pulse = 0;
  sConfigOC.OCPolarity = TIM_OCPOLARITY_HIGH;
  sConfigOC.OCFastMode = TIM_OCFAST_DISABLE;
  if (HAL_TIM_PWM_ConfigChannel(&htim5, &sConfigOC, TIM_CHANNEL_4) != HAL_OK)
  {
    Error_Handler();
  }
  HAL_TIM_MspPostInit(&htim5);

}

static void MX_TIM13_Init(void)
{

  htim13.Instance = TIM13;
  htim13.Init.Prescaler = 99;
  htim13.Init.CounterMode = TIM_COUNTERMODE_UP;
  htim13.Init.Period = 65535;
  htim13.Init.ClockDivision = TIM_CLOCKDIVISION_DIV1;
  htim13.Init.AutoReloadPreload = TIM_AUTORELOAD_PRELOAD_DISABLE;
  if (HAL_TIM_Base_Init(&htim13) != HAL_OK)
  {
    Error_Handler();
  }

}

static void MX_UART4_Init(void)
{

  huart4.Instance = UART4;
  huart4.Init.BaudRate = 115200;
  huart4.Init.WordLength = UART_WORDLENGTH_8B;
  huart4.Init.StopBits = UART_STOPBITS_1;
  huart4.Init.Parity = UART_PARITY_NONE;
  huart4.Init.Mode = UART_MODE_TX_RX;
  huart4.Init.HwFlowCtl = UART_HWCONTROL_NONE;
  huart4.Init.OverSampling = UART_OVERSAMPLING_16;
  huart4.Init.OneBitSampling = UART_ONE_BIT_SAMPLE_DISABLE;
  huart4.Init.ClockPrescaler = UART_PRESCALER_DIV1;
  huart4.AdvancedInit.AdvFeatureInit = UART_ADVFEATURE_NO_INIT;
  if (HAL_UART_Init(&huart4) != HAL_OK)
  {
    Error_Handler();
  }
  if (HAL_UARTEx_SetTxFifoThreshold(&huart4, UART_TXFIFO_THRESHOLD_1_8) != HAL_OK)
  {
    Error_Handler();
  }
  if (HAL_UARTEx_SetRxFifoThreshold(&huart4, UART_RXFIFO_THRESHOLD_1_8) != HAL_OK)
  {
    Error_Handler();
  }
  if (HAL_UARTEx_DisableFifoMode(&huart4) != HAL_OK)
  {
    Error_Handler();
  }

}

static void MX_USART6_UART_Init(void)
{

  huart6.Instance = USART6;
  huart6.Init.BaudRate = 115200;
  huart6.Init.WordLength = UART_WORDLENGTH_8B;
  huart6.Init.StopBits = UART_STOPBITS_1;
  huart6.Init.Parity = UART_PARITY_NONE;
  huart6.Init.Mode = UART_MODE_TX_RX;
  huart6.Init.HwFlowCtl = UART_HWCONTROL_NONE;
  huart6.Init.OverSampling = UART_OVERSAMPLING_16;
  huart6.Init.OneBitSampling = UART_ONE_BIT_SAMPLE_DISABLE;
  huart6.Init.ClockPrescaler = UART_PRESCALER_DIV1;
  huart6.AdvancedInit.AdvFeatureInit = UART_ADVFEATURE_NO_INIT;
  if (HAL_UART_Init(&huart6) != HAL_OK)
  {
    Error_Handler();
  }
  if (HAL_UARTEx_SetTxFifoThreshold(&huart6, UART_TXFIFO_THRESHOLD_1_8) != HAL_OK)
  {
    Error_Handler();
  }
  if (HAL_UARTEx_SetRxFifoThreshold(&huart6, UART_RXFIFO_THRESHOLD_1_8) != HAL_OK)
  {
    Error_Handler();
  }
  if (HAL_UARTEx_DisableFifoMode(&huart6) != HAL_OK)
  {
    Error_Handler();
  }

}

static void MX_DMA_Init(void)
{

  /* DMA controller clock enable */
  __HAL_RCC_DMA1_CLK_ENABLE();
  __HAL_RCC_DMA2_CLK_ENABLE();

  /* DMA interrupt init */
  /* DMA1_Stream0_IRQn interrupt configuration */
  HAL_NVIC_SetPriority(DMA1_Stream0_IRQn, 0, 0);
  HAL_NVIC_EnableIRQ(DMA1_Stream0_IRQn);
  /* DMA1_Stream1_IRQn interrupt configuration */
  HAL_NVIC_SetPriority(DMA1_Stream1_IRQn, 0, 0);
  HAL_NVIC_EnableIRQ(DMA1_Stream1_IRQn);
  /* DMA1_Stream2_IRQn interrupt configuration */
  HAL_NVIC_SetPriority(DMA1_Stream2_IRQn, 0, 0);
  HAL_NVIC_EnableIRQ(DMA1_Stream2_IRQn);
  /* DMA1_Stream3_IRQn interrupt configuration */
  HAL_NVIC_SetPriority(DMA1_Stream3_IRQn, 0, 0);
  HAL_NVIC_EnableIRQ(DMA1_Stream3_IRQn);
  /* DMA1_Stream4_IRQn interrupt configuration */
  HAL_NVIC_SetPriority(DMA1_Stream4_IRQn, 0, 0);
  HAL_NVIC_EnableIRQ(DMA1_Stream4_IRQn);
  /* DMA1_Stream5_IRQn interrupt configuration */
  HAL_NVIC_SetPriority(DMA1_Stream5_IRQn, 0, 0);
  HAL_NVIC_EnableIRQ(DMA1_Stream5_IRQn);
  /* DMA2_Stream7_IRQn interrupt configuration */
  HAL_NVIC_SetPriority(DMA2_Stream7_IRQn, 0, 0);
  HAL_NVIC_EnableIRQ(DMA2_Stream7_IRQn);

}

static void MX_GPIO_Init(void)
{
  GPIO_InitTypeDef GPIO_InitStruct = {0};

  /* GPIO Ports Clock Enable */
  __HAL_RCC_GPIOE_CLK_ENABLE();
  __HAL_RCC_GPIOF_CLK_ENABLE();
  __HAL_RCC_GPIOC_CLK_ENABLE();
  __HAL_RCC_GPIOA_CLK_ENABLE();
  __HAL_RCC_GPIOB_CLK_ENABLE();
  __HAL_RCC_GPIOG_CLK_ENABLE();
  __HAL_RCC_GPIOD_CLK_ENABLE();

  /*Configure GPIO pin Output Level */
  HAL_GPIO_WritePin(GPIOE, GPIO_PIN_2|PYRO6_Pin|PYRO7_Pin|PYRO8_Pin, GPIO_PIN_RESET);

  /*Configure GPIO pin Output Level */
  HAL_GPIO_WritePin(GPIOA, ARM1_Pin|GPIO_PIN_15, GPIO_PIN_RESET);

  /*Configure GPIO pin Output Level */
  HAL_GPIO_WritePin(GPIOC, GPIO_PIN_4|GPIO_PIN_5, GPIO_PIN_RESET);

  /*Configure GPIO pin Output Level */
  HAL_GPIO_WritePin(GPIOB, GPIO_PIN_0|PYRO1_Pin, GPIO_PIN_RESET);

  /*Configure GPIO pin Output Level */
  HAL_GPIO_WritePin(GPIOF, PYRO2_Pin|PYRO3_Pin|PYRO4_Pin, GPIO_PIN_RESET);

  /*Configure GPIO pin Output Level */
  HAL_GPIO_WritePin(GPIOG, PYRO5_Pin|GPIO_PIN_2|GPIO_PIN_3, GPIO_PIN_RESET);

  /*Configure GPIO pin Output Level */
  HAL_GPIO_WritePin(GPIOD, GPIO_PIN_8|GPIO_PIN_9|GPIO_PIN_10, GPIO_PIN_SET);

  /*Configure GPIO pin Output Level */
  HAL_GPIO_WritePin(GPIOD, GPIO_PIN_0, GPIO_PIN_RESET);

  /*Configure GPIO pins : PE2 PYRO6_Pin PYRO7_Pin PYRO8_Pin */
  GPIO_InitStruct.Pin = GPIO_PIN_2|PYRO6_Pin|PYRO7_Pin|PYRO8_Pin;
  GPIO_InitStruct.Mode = GPIO_MODE_OUTPUT_PP;
  GPIO_InitStruct.Pull = GPIO_NOPULL;
  GPIO_InitStruct.Speed = GPIO_SPEED_FREQ_LOW;
  HAL_GPIO_Init(GPIOE, &GPIO_InitStruct);

  /*Configure GPIO pins : ARM1_Pin PA15 */
  GPIO_InitStruct.Pin = ARM1_Pin|GPIO_PIN_15;
  GPIO_InitStruct.Mode = GPIO_MODE_OUTPUT_PP;
  GPIO_InitStruct.Pull = GPIO_NOPULL;
  GPIO_InitStruct.Speed = GPIO_SPEED_FREQ_LOW;
  HAL_GPIO_Init(GPIOA, &GPIO_InitStruct);

  /*Configure GPIO pins : PC4 PC5 */
  GPIO_InitStruct.Pin = GPIO_PIN_4|GPIO_PIN_5;
  GPIO_InitStruct.Mode = GPIO_MODE_OUTPUT_PP;
  GPIO_InitStruct.Pull = GPIO_NOPULL;
  GPIO_InitStruct.Speed = GPIO_SPEED_FREQ_LOW;
  HAL_GPIO_Init(GPIOC, &GPIO_InitStruct);

  /*Configure GPIO pins : PB0 PYRO1_Pin */
  GPIO_InitStruct.Pin = GPIO_PIN_0|PYRO1_Pin;
  GPIO_InitStruct.Mode = GPIO_MODE_OUTPUT_PP;
  GPIO_InitStruct.Pull = GPIO_NOPULL;
  GPIO_InitStruct.Speed = GPIO_SPEED_FREQ_LOW;
  HAL_GPIO_Init(GPIOB, &GPIO_InitStruct);

  /*Configure GPIO pin : CONT1_Pin */
  GPIO_InitStruct.Pin = CONT1_Pin;
  GPIO_InitStruct.Mode = GPIO_MODE_INPUT;
  GPIO_InitStruct.Pull = GPIO_PULLUP;
  HAL_GPIO_Init(CONT1_GPIO_Port, &GPIO_InitStruct);

  /*Configure GPIO pins : PYRO2_Pin PYRO3_Pin PYRO4_Pin */
  GPIO_InitStruct.Pin = PYRO2_Pin|PYRO3_Pin|PYRO4_Pin;
  GPIO_InitStruct.Mode = GPIO_MODE_OUTPUT_PP;
  GPIO_InitStruct.Pull = GPIO_NOPULL;
  GPIO_InitStruct.Speed = GPIO_SPEED_FREQ_LOW;
  HAL_GPIO_Init(GPIOF, &GPIO_InitStruct);

  /*Configure GPIO pins : CONT2_Pin CONT3_Pin */
  GPIO_InitStruct.Pin = CONT2_Pin|CONT3_Pin;
  GPIO_InitStruct.Mode = GPIO_MODE_INPUT;
  GPIO_InitStruct.Pull = GPIO_PULLUP;
  HAL_GPIO_Init(GPIOF, &GPIO_InitStruct);

  /*Configure GPIO pin : CONT4_Pin */
  GPIO_InitStruct.Pin = CONT4_Pin;
  GPIO_InitStruct.Mode = GPIO_MODE_INPUT;
  GPIO_InitStruct.Pull = GPIO_PULLUP;
  HAL_GPIO_Init(CONT4_GPIO_Port, &GPIO_InitStruct);

  /*Configure GPIO pins : PYRO5_Pin PG2 PG3 */
  GPIO_InitStruct.Pin = PYRO5_Pin|GPIO_PIN_2|GPIO_PIN_3;
  GPIO_InitStruct.Mode = GPIO_MODE_OUTPUT_PP;
  GPIO_InitStruct.Pull = GPIO_NOPULL;
  GPIO_InitStruct.Speed = GPIO_SPEED_FREQ_LOW;
  HAL_GPIO_Init(GPIOG, &GPIO_InitStruct);

  /*Configure GPIO pins : CONT5_Pin CONT6_Pin CONT7_Pin CONT8_Pin */
  GPIO_InitStruct.Pin = CONT5_Pin|CONT6_Pin|CONT7_Pin|CONT8_Pin;
  GPIO_InitStruct.Mode = GPIO_MODE_INPUT;
  GPIO_InitStruct.Pull = GPIO_PULLUP;
  HAL_GPIO_Init(GPIOE, &GPIO_InitStruct);

  /*Configure GPIO pins : PD8 PD9 PD10 PD0 */
  GPIO_InitStruct.Pin = GPIO_PIN_8|GPIO_PIN_9|GPIO_PIN_10|GPIO_PIN_0;
  GPIO_InitStruct.Mode = GPIO_MODE_OUTPUT_PP;
  GPIO_InitStruct.Pull = GPIO_NOPULL;
  GPIO_InitStruct.Speed = GPIO_SPEED_FREQ_LOW;
  HAL_GPIO_Init(GPIOD, &GPIO_InitStruct);

  /*Configure GPIO pin : Servo_ARM_CHECK_Pin */
  GPIO_InitStruct.Pin = Servo_ARM_CHECK_Pin;
  GPIO_InitStruct.Mode = GPIO_MODE_INPUT;
  GPIO_InitStruct.Pull = GPIO_NOPULL;
  HAL_GPIO_Init(Servo_ARM_CHECK_GPIO_Port, &GPIO_InitStruct);

  /*Configure GPIO pin : PA8 */
  GPIO_InitStruct.Pin = GPIO_PIN_8;
  GPIO_InitStruct.Mode = GPIO_MODE_AF_PP;
  GPIO_InitStruct.Pull = GPIO_NOPULL;
  GPIO_InitStruct.Speed = GPIO_SPEED_FREQ_LOW;
  GPIO_InitStruct.Alternate = GPIO_AF0_MCO;
  HAL_GPIO_Init(GPIOA, &GPIO_InitStruct);

}

/* USER CODE BEGIN 4 */

void HAL_I2C_MasterRxCpltCallback(I2C_HandleTypeDef *hi2c) {
//MAX_M10s_irq_handler(hi2c);
}

void HAL_ADC_ConvHalfCpltCallback(ADC_HandleTypeDef *hadc) {
  DMA_data = read_Data;
  char data_gyro[100];
  sprintf(data_gyro, "a\n");
  CDC_Transmit_HS(data_gyro, strlen(data_gyro));
}
/* USER CODE END 4 */

void Error_Handler(void)
{
__disable_irq();
while (1) {
}
}
